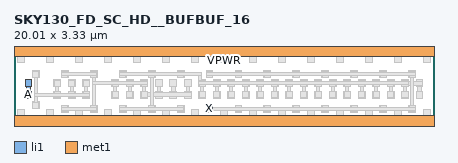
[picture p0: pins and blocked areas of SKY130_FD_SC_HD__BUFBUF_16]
MACRO SKY130_FD_SC_HD__BUFBUF_16
 CLASS CORE ;
 FOREIGN SKY130_FD_SC_HD__BUFBUF_16 0 0 ;
 SIZE 20.01 BY 3.33 ;
 ORIGIN 0 0 ;
 SYMMETRY X Y R90 ;
 SITE unit ;
  PIN VPWR
   DIRECTION INOUT ;
   USE POWER ;
   SHAPE ABUTMENT ;
    PORT
     CLASS CORE ;
       LAYER li1 ;
        RECT 0.00000000 3.09000000 20.01000000 3.57000000 ;
       LAYER met1 ;
        RECT 0.00000000 3.09000000 20.01000000 3.57000000 ;
    END
  END VPWR

  PIN VGND
   DIRECTION INOUT ;
   USE POWER ;
   SHAPE ABUTMENT ;
    PORT
     CLASS CORE ;
       LAYER li1 ;
        RECT 0.00000000 -0.24000000 20.01000000 0.24000000 ;
       LAYER met1 ;
        RECT 0.00000000 -0.24000000 20.01000000 0.24000000 ;
    END
  END VGND

  PIN X
   DIRECTION INOUT ;
   USE SIGNAL ;
   SHAPE ABUTMENT ;
    PORT
     CLASS CORE ;
       LAYER li1 ;
        RECT 9.15000000 0.42000000 9.48000000 0.75000000 ;
    END
  END X

  PIN A
   DIRECTION INOUT ;
   USE SIGNAL ;
   SHAPE ABUTMENT ;
    PORT
     CLASS CORE ;
       LAYER li1 ;
        RECT 0.52500000 1.09500000 0.85500000 1.42500000 ;
        RECT 0.60500000 1.42500000 0.77500000 1.63500000 ;
        RECT 0.52500000 1.63500000 0.85500000 1.96500000 ;
    END
  END A

 OBS
    LAYER polycont ;
     RECT 0.60500000 1.17500000 0.77500000 1.34500000 ;
     RECT 1.98500000 1.17500000 2.15500000 1.34500000 ;
     RECT 2.67500000 1.17500000 2.84500000 1.34500000 ;
     RECT 3.36500000 1.17500000 3.53500000 1.34500000 ;
     RECT 4.74500000 1.17500000 4.91500000 1.34500000 ;
     RECT 5.43500000 1.17500000 5.60500000 1.34500000 ;
     RECT 6.12500000 1.17500000 6.29500000 1.34500000 ;
     RECT 6.81500000 1.17500000 6.98500000 1.34500000 ;
     RECT 7.50500000 1.17500000 7.67500000 1.34500000 ;
     RECT 8.19500000 1.17500000 8.36500000 1.34500000 ;
     RECT 8.88500000 1.17500000 9.05500000 1.34500000 ;
     RECT 9.57500000 1.17500000 9.74500000 1.34500000 ;
     RECT 10.26500000 1.17500000 10.43500000 1.34500000 ;
     RECT 10.95500000 1.17500000 11.12500000 1.34500000 ;
     RECT 11.64500000 1.17500000 11.81500000 1.34500000 ;
     RECT 12.33500000 1.17500000 12.50500000 1.34500000 ;
     RECT 13.02500000 1.17500000 13.19500000 1.34500000 ;
     RECT 13.71500000 1.17500000 13.88500000 1.34500000 ;
     RECT 14.40500000 1.17500000 14.57500000 1.34500000 ;
     RECT 15.09500000 1.17500000 15.26500000 1.34500000 ;
     RECT 15.78500000 1.17500000 15.95500000 1.34500000 ;
     RECT 16.47500000 1.17500000 16.64500000 1.34500000 ;
     RECT 17.16500000 1.17500000 17.33500000 1.34500000 ;
     RECT 17.85500000 1.17500000 18.02500000 1.34500000 ;
     RECT 18.54500000 1.17500000 18.71500000 1.34500000 ;
     RECT 19.23500000 1.17500000 19.40500000 1.34500000 ;
     RECT 0.60500000 1.71500000 0.77500000 1.88500000 ;
     RECT 1.98500000 1.71500000 2.15500000 1.88500000 ;
     RECT 2.67500000 1.71500000 2.84500000 1.88500000 ;
     RECT 3.36500000 1.71500000 3.53500000 1.88500000 ;
     RECT 4.74500000 1.71500000 4.91500000 1.88500000 ;
     RECT 5.43500000 1.71500000 5.60500000 1.88500000 ;
     RECT 6.12500000 1.71500000 6.29500000 1.88500000 ;
     RECT 6.81500000 1.71500000 6.98500000 1.88500000 ;
     RECT 7.50500000 1.71500000 7.67500000 1.88500000 ;
     RECT 8.19500000 1.71500000 8.36500000 1.88500000 ;
     RECT 8.88500000 1.71500000 9.05500000 1.88500000 ;
     RECT 9.57500000 1.71500000 9.74500000 1.88500000 ;
     RECT 10.26500000 1.71500000 10.43500000 1.88500000 ;
     RECT 10.95500000 1.71500000 11.12500000 1.88500000 ;
     RECT 11.64500000 1.71500000 11.81500000 1.88500000 ;
     RECT 12.33500000 1.71500000 12.50500000 1.88500000 ;
     RECT 13.02500000 1.71500000 13.19500000 1.88500000 ;
     RECT 13.71500000 1.71500000 13.88500000 1.88500000 ;
     RECT 14.40500000 1.71500000 14.57500000 1.88500000 ;
     RECT 15.09500000 1.71500000 15.26500000 1.88500000 ;
     RECT 15.78500000 1.71500000 15.95500000 1.88500000 ;
     RECT 16.47500000 1.71500000 16.64500000 1.88500000 ;
     RECT 17.16500000 1.71500000 17.33500000 1.88500000 ;
     RECT 17.85500000 1.71500000 18.02500000 1.88500000 ;
     RECT 18.54500000 1.71500000 18.71500000 1.88500000 ;
     RECT 19.23500000 1.71500000 19.40500000 1.88500000 ;

    LAYER pdiffc ;
     RECT 0.95000000 2.15000000 1.12000000 2.32000000 ;
     RECT 2.33000000 2.15000000 2.50000000 2.32000000 ;
     RECT 3.71000000 2.15000000 3.88000000 2.32000000 ;
     RECT 5.09000000 2.15000000 5.26000000 2.32000000 ;
     RECT 6.47000000 2.15000000 6.64000000 2.32000000 ;
     RECT 7.85000000 2.15000000 8.02000000 2.32000000 ;
     RECT 9.23000000 2.15000000 9.40000000 2.32000000 ;
     RECT 10.61000000 2.15000000 10.78000000 2.32000000 ;
     RECT 11.99000000 2.15000000 12.16000000 2.32000000 ;
     RECT 13.37000000 2.15000000 13.54000000 2.32000000 ;
     RECT 14.75000000 2.15000000 14.92000000 2.32000000 ;
     RECT 16.13000000 2.15000000 16.30000000 2.32000000 ;
     RECT 17.51000000 2.15000000 17.68000000 2.32000000 ;
     RECT 18.89000000 2.15000000 19.06000000 2.32000000 ;
     RECT 0.26000000 2.86000000 0.43000000 3.03000000 ;
     RECT 1.64000000 2.86000000 1.81000000 3.03000000 ;
     RECT 3.02000000 2.86000000 3.19000000 3.03000000 ;
     RECT 4.40000000 2.86000000 4.57000000 3.03000000 ;
     RECT 5.78000000 2.86000000 5.95000000 3.03000000 ;
     RECT 7.16000000 2.86000000 7.33000000 3.03000000 ;
     RECT 8.54000000 2.86000000 8.71000000 3.03000000 ;
     RECT 9.92000000 2.86000000 10.09000000 3.03000000 ;
     RECT 11.30000000 2.86000000 11.47000000 3.03000000 ;
     RECT 12.68000000 2.86000000 12.85000000 3.03000000 ;
     RECT 14.06000000 2.86000000 14.23000000 3.03000000 ;
     RECT 15.44000000 2.86000000 15.61000000 3.03000000 ;
     RECT 16.82000000 2.86000000 16.99000000 3.03000000 ;
     RECT 18.20000000 2.86000000 18.37000000 3.03000000 ;
     RECT 19.58000000 2.86000000 19.75000000 3.03000000 ;

    LAYER ndiffc ;
     RECT 0.26000000 0.30000000 0.43000000 0.47000000 ;
     RECT 1.64000000 0.30000000 1.81000000 0.47000000 ;
     RECT 3.02000000 0.30000000 3.19000000 0.47000000 ;
     RECT 4.40000000 0.30000000 4.57000000 0.47000000 ;
     RECT 5.78000000 0.30000000 5.95000000 0.47000000 ;
     RECT 7.16000000 0.30000000 7.33000000 0.47000000 ;
     RECT 8.54000000 0.30000000 8.71000000 0.47000000 ;
     RECT 9.92000000 0.30000000 10.09000000 0.47000000 ;
     RECT 11.30000000 0.30000000 11.47000000 0.47000000 ;
     RECT 12.68000000 0.30000000 12.85000000 0.47000000 ;
     RECT 14.06000000 0.30000000 14.23000000 0.47000000 ;
     RECT 15.44000000 0.30000000 15.61000000 0.47000000 ;
     RECT 16.82000000 0.30000000 16.99000000 0.47000000 ;
     RECT 18.20000000 0.30000000 18.37000000 0.47000000 ;
     RECT 19.58000000 0.30000000 19.75000000 0.47000000 ;
     RECT 2.33000000 0.50000000 2.50000000 0.67000000 ;
     RECT 3.71000000 0.50000000 3.88000000 0.67000000 ;
     RECT 5.09000000 0.50000000 5.26000000 0.67000000 ;
     RECT 6.47000000 0.50000000 6.64000000 0.67000000 ;
     RECT 7.85000000 0.50000000 8.02000000 0.67000000 ;
     RECT 9.23000000 0.50000000 9.40000000 0.67000000 ;
     RECT 10.61000000 0.50000000 10.78000000 0.67000000 ;
     RECT 11.99000000 0.50000000 12.16000000 0.67000000 ;
     RECT 13.37000000 0.50000000 13.54000000 0.67000000 ;
     RECT 14.75000000 0.50000000 14.92000000 0.67000000 ;
     RECT 16.13000000 0.50000000 16.30000000 0.67000000 ;
     RECT 17.51000000 0.50000000 17.68000000 0.67000000 ;
     RECT 18.89000000 0.50000000 19.06000000 0.67000000 ;
     RECT 0.95000000 0.66000000 1.12000000 0.83000000 ;

    LAYER li1 ;
     RECT 0.00000000 -0.24000000 20.01000000 0.24000000 ;
     RECT 9.84000000 0.24000000 10.17000000 0.55000000 ;
     RECT 9.84000000 2.78000000 10.17000000 3.09000000 ;
     RECT 0.00000000 3.09000000 20.01000000 3.57000000 ;
     RECT 13.98000000 0.24000000 14.31000000 0.55000000 ;
     RECT 15.36000000 0.24000000 15.69000000 0.55000000 ;
     RECT 16.74000000 0.24000000 17.07000000 0.55000000 ;
     RECT 18.12000000 0.24000000 18.45000000 0.55000000 ;
     RECT 19.50000000 0.24000000 19.83000000 0.55000000 ;
     RECT 10.53000000 0.42000000 10.86000000 0.75000000 ;
     RECT 11.91000000 0.42000000 12.24000000 0.75000000 ;
     RECT 13.29000000 0.42000000 13.62000000 0.75000000 ;
     RECT 14.67000000 0.42000000 15.00000000 0.75000000 ;
     RECT 16.05000000 0.42000000 16.38000000 0.75000000 ;
     RECT 17.43000000 0.42000000 17.76000000 0.75000000 ;
     RECT 18.81000000 0.42000000 19.14000000 0.75000000 ;
     RECT 10.18500000 1.09500000 10.51500000 1.42500000 ;
     RECT 10.87500000 1.09500000 11.20500000 1.42500000 ;
     RECT 11.56500000 1.09500000 11.89500000 1.42500000 ;
     RECT 12.25500000 1.09500000 12.58500000 1.42500000 ;
     RECT 12.94500000 1.09500000 13.27500000 1.42500000 ;
     RECT 13.63500000 1.09500000 13.96500000 1.42500000 ;
     RECT 14.32500000 1.09500000 14.65500000 1.42500000 ;
     RECT 15.01500000 1.09500000 15.34500000 1.42500000 ;
     RECT 15.70500000 1.09500000 16.03500000 1.42500000 ;
     RECT 16.39500000 1.09500000 16.72500000 1.42500000 ;
     RECT 17.08500000 1.09500000 17.41500000 1.42500000 ;
     RECT 17.77500000 1.09500000 18.10500000 1.42500000 ;
     RECT 18.46500000 1.09500000 18.79500000 1.42500000 ;
     RECT 10.18500000 1.63500000 10.51500000 1.96500000 ;
     RECT 10.87500000 1.63500000 11.20500000 1.96500000 ;
     RECT 11.56500000 1.63500000 11.89500000 1.96500000 ;
     RECT 12.25500000 1.63500000 12.58500000 1.96500000 ;
     RECT 12.94500000 1.63500000 13.27500000 1.96500000 ;
     RECT 13.63500000 1.63500000 13.96500000 1.96500000 ;
     RECT 14.32500000 1.63500000 14.65500000 1.96500000 ;
     RECT 15.01500000 1.63500000 15.34500000 1.96500000 ;
     RECT 15.70500000 1.63500000 16.03500000 1.96500000 ;
     RECT 16.39500000 1.63500000 16.72500000 1.96500000 ;
     RECT 17.08500000 1.63500000 17.41500000 1.96500000 ;
     RECT 17.77500000 1.63500000 18.10500000 1.96500000 ;
     RECT 19.15500000 1.09500000 19.48500000 1.42500000 ;
     RECT 19.23500000 1.42500000 19.40500000 1.63500000 ;
     RECT 18.46500000 1.63500000 18.79500000 1.71500000 ;
     RECT 19.15500000 1.63500000 19.48500000 1.71500000 ;
     RECT 18.46500000 1.71500000 19.48500000 1.88500000 ;
     RECT 18.46500000 1.88500000 18.79500000 1.96500000 ;
     RECT 19.15500000 1.88500000 19.48500000 1.96500000 ;
     RECT 10.53000000 2.07000000 10.86000000 2.40000000 ;
     RECT 11.91000000 2.07000000 12.24000000 2.40000000 ;
     RECT 13.29000000 2.07000000 13.62000000 2.40000000 ;
     RECT 14.67000000 2.07000000 15.00000000 2.40000000 ;
     RECT 16.05000000 2.07000000 16.38000000 2.40000000 ;
     RECT 17.43000000 2.07000000 17.76000000 2.40000000 ;
     RECT 18.81000000 2.07000000 19.14000000 2.40000000 ;
     RECT 11.22000000 0.24000000 11.55000000 0.55000000 ;
     RECT 11.22000000 2.78000000 11.55000000 3.09000000 ;
     RECT 12.60000000 2.78000000 12.93000000 3.09000000 ;
     RECT 13.98000000 2.78000000 14.31000000 3.09000000 ;
     RECT 15.36000000 2.78000000 15.69000000 3.09000000 ;
     RECT 16.74000000 2.78000000 17.07000000 3.09000000 ;
     RECT 18.12000000 2.78000000 18.45000000 3.09000000 ;
     RECT 19.50000000 2.78000000 19.83000000 3.09000000 ;
     RECT 12.60000000 0.24000000 12.93000000 0.55000000 ;
     RECT 6.04500000 1.34500000 6.37500000 1.42500000 ;
     RECT 6.73500000 1.34500000 7.06500000 1.42500000 ;
     RECT 7.42500000 1.34500000 7.75500000 1.42500000 ;
     RECT 8.11500000 1.34500000 8.44500000 1.42500000 ;
     RECT 6.81500000 1.42500000 6.98500000 1.63500000 ;
     RECT 7.50500000 1.42500000 7.67500000 1.63500000 ;
     RECT 8.19500000 1.42500000 8.36500000 1.63500000 ;
     RECT 6.73500000 1.63500000 7.06500000 1.96500000 ;
     RECT 7.42500000 1.63500000 7.75500000 1.96500000 ;
     RECT 8.11500000 1.63500000 8.44500000 1.96500000 ;
     RECT 8.80500000 1.63500000 9.13500000 1.96500000 ;
     RECT 9.49500000 1.63500000 9.82500000 1.96500000 ;
     RECT 0.87000000 0.58000000 1.20000000 0.91000000 ;
     RECT 1.90500000 1.09500000 2.23500000 1.42500000 ;
     RECT 2.59500000 1.09500000 2.92500000 1.42500000 ;
     RECT 3.28500000 1.09500000 3.61500000 1.42500000 ;
     RECT 4.66500000 1.09500000 4.99500000 1.42500000 ;
     RECT 5.35500000 1.09500000 5.68500000 1.42500000 ;
     RECT 8.80500000 1.09500000 9.13500000 1.42500000 ;
     RECT 9.49500000 1.09500000 9.82500000 1.42500000 ;
     RECT 2.25000000 0.42000000 2.58000000 0.75000000 ;
     RECT 3.63000000 0.42000000 3.96000000 0.75000000 ;
     RECT 5.01000000 0.42000000 5.34000000 0.75000000 ;
     RECT 6.39000000 0.42000000 6.72000000 0.75000000 ;
     RECT 7.77000000 0.42000000 8.10000000 0.75000000 ;
     RECT 9.15000000 0.42000000 9.48000000 0.75000000 ;
     RECT 1.56000000 0.24000000 1.89000000 0.55000000 ;
     RECT 2.94000000 0.24000000 3.27000000 0.55000000 ;
     RECT 4.32000000 0.24000000 4.65000000 0.55000000 ;
     RECT 5.70000000 0.24000000 6.03000000 0.55000000 ;
     RECT 7.08000000 0.24000000 7.41000000 0.55000000 ;
     RECT 0.87000000 2.07000000 1.20000000 2.40000000 ;
     RECT 2.25000000 2.07000000 2.58000000 2.40000000 ;
     RECT 3.63000000 2.07000000 3.96000000 2.40000000 ;
     RECT 5.01000000 2.07000000 5.34000000 2.40000000 ;
     RECT 6.39000000 2.07000000 6.72000000 2.40000000 ;
     RECT 7.77000000 2.07000000 8.10000000 2.40000000 ;
     RECT 9.15000000 2.07000000 9.48000000 2.40000000 ;
     RECT 8.46000000 0.24000000 8.79000000 0.55000000 ;
     RECT 0.18000000 0.24000000 0.51000000 0.55000000 ;
     RECT 0.52500000 1.09500000 0.85500000 1.42500000 ;
     RECT 0.60500000 1.42500000 0.77500000 1.63500000 ;
     RECT 0.52500000 1.63500000 0.85500000 1.96500000 ;
     RECT 1.90500000 1.63500000 2.23500000 1.96500000 ;
     RECT 2.59500000 1.63500000 2.92500000 1.96500000 ;
     RECT 0.18000000 2.78000000 0.51000000 3.09000000 ;
     RECT 1.56000000 2.78000000 1.89000000 3.09000000 ;
     RECT 2.94000000 2.78000000 3.27000000 3.09000000 ;
     RECT 4.32000000 2.78000000 4.65000000 3.09000000 ;
     RECT 5.70000000 2.78000000 6.03000000 3.09000000 ;
     RECT 7.08000000 2.78000000 7.41000000 3.09000000 ;
     RECT 8.46000000 2.78000000 8.79000000 3.09000000 ;
     RECT 3.28500000 1.63500000 3.61500000 1.96500000 ;
     RECT 4.66500000 1.63500000 4.99500000 1.96500000 ;
     RECT 5.35500000 1.63500000 5.68500000 1.96500000 ;
     RECT 6.04500000 1.63500000 6.37500000 1.96500000 ;
     RECT 6.04500000 1.09500000 6.37500000 1.17500000 ;
     RECT 6.73500000 1.09500000 7.06500000 1.17500000 ;
     RECT 7.42500000 1.09500000 7.75500000 1.17500000 ;
     RECT 8.11500000 1.09500000 8.44500000 1.17500000 ;
     RECT 6.04500000 1.17500000 8.44500000 1.34500000 ;

    LAYER viali ;
     RECT 9.92000000 -0.08500000 10.09000000 0.08500000 ;
     RECT 2.33000000 0.50000000 2.50000000 0.67000000 ;
     RECT 3.71000000 0.50000000 3.88000000 0.67000000 ;
     RECT 5.09000000 0.50000000 5.26000000 0.67000000 ;
     RECT 6.47000000 0.50000000 6.64000000 0.67000000 ;
     RECT 7.85000000 0.50000000 8.02000000 0.67000000 ;
     RECT 9.23000000 0.50000000 9.40000000 0.67000000 ;
     RECT 10.61000000 0.50000000 10.78000000 0.67000000 ;
     RECT 11.99000000 0.50000000 12.16000000 0.67000000 ;
     RECT 13.37000000 0.50000000 13.54000000 0.67000000 ;
     RECT 14.75000000 0.50000000 14.92000000 0.67000000 ;
     RECT 16.13000000 0.50000000 16.30000000 0.67000000 ;
     RECT 17.51000000 0.50000000 17.68000000 0.67000000 ;
     RECT 18.89000000 0.50000000 19.06000000 0.67000000 ;
     RECT 0.95000000 0.66000000 1.12000000 0.83000000 ;
     RECT 1.98500000 1.17500000 2.15500000 1.34500000 ;
     RECT 2.67500000 1.17500000 2.84500000 1.34500000 ;
     RECT 3.36500000 1.17500000 3.53500000 1.34500000 ;
     RECT 4.74500000 1.17500000 4.91500000 1.34500000 ;
     RECT 5.43500000 1.17500000 5.60500000 1.34500000 ;
     RECT 6.12500000 1.17500000 6.29500000 1.34500000 ;
     RECT 8.88500000 1.17500000 9.05500000 1.34500000 ;
     RECT 9.57500000 1.17500000 9.74500000 1.34500000 ;
     RECT 10.26500000 1.17500000 10.43500000 1.34500000 ;
     RECT 10.95500000 1.17500000 11.12500000 1.34500000 ;
     RECT 11.64500000 1.17500000 11.81500000 1.34500000 ;
     RECT 12.33500000 1.17500000 12.50500000 1.34500000 ;
     RECT 13.02500000 1.17500000 13.19500000 1.34500000 ;
     RECT 13.71500000 1.17500000 13.88500000 1.34500000 ;
     RECT 14.40500000 1.17500000 14.57500000 1.34500000 ;
     RECT 15.09500000 1.17500000 15.26500000 1.34500000 ;
     RECT 15.78500000 1.17500000 15.95500000 1.34500000 ;
     RECT 16.47500000 1.17500000 16.64500000 1.34500000 ;
     RECT 17.16500000 1.17500000 17.33500000 1.34500000 ;
     RECT 17.85500000 1.17500000 18.02500000 1.34500000 ;
     RECT 18.54500000 1.17500000 18.71500000 1.34500000 ;
     RECT 1.98500000 1.71500000 2.15500000 1.88500000 ;
     RECT 2.67500000 1.71500000 2.84500000 1.88500000 ;
     RECT 3.36500000 1.71500000 3.53500000 1.88500000 ;
     RECT 4.74500000 1.71500000 4.91500000 1.88500000 ;
     RECT 5.43500000 1.71500000 5.60500000 1.88500000 ;
     RECT 6.12500000 1.71500000 6.29500000 1.88500000 ;
     RECT 8.88500000 1.71500000 9.05500000 1.88500000 ;
     RECT 9.57500000 1.71500000 9.74500000 1.88500000 ;
     RECT 10.26500000 1.71500000 10.43500000 1.88500000 ;
     RECT 10.95500000 1.71500000 11.12500000 1.88500000 ;
     RECT 11.64500000 1.71500000 11.81500000 1.88500000 ;
     RECT 12.33500000 1.71500000 12.50500000 1.88500000 ;
     RECT 13.02500000 1.71500000 13.19500000 1.88500000 ;
     RECT 13.71500000 1.71500000 13.88500000 1.88500000 ;
     RECT 14.40500000 1.71500000 14.57500000 1.88500000 ;
     RECT 15.09500000 1.71500000 15.26500000 1.88500000 ;
     RECT 15.78500000 1.71500000 15.95500000 1.88500000 ;
     RECT 16.47500000 1.71500000 16.64500000 1.88500000 ;
     RECT 17.16500000 1.71500000 17.33500000 1.88500000 ;
     RECT 17.85500000 1.71500000 18.02500000 1.88500000 ;
     RECT 18.54500000 1.71500000 18.71500000 1.88500000 ;
     RECT 0.95000000 2.15000000 1.12000000 2.32000000 ;
     RECT 2.33000000 2.15000000 2.50000000 2.32000000 ;
     RECT 3.71000000 2.15000000 3.88000000 2.32000000 ;
     RECT 5.09000000 2.15000000 5.26000000 2.32000000 ;
     RECT 6.47000000 2.15000000 6.64000000 2.32000000 ;
     RECT 7.85000000 2.15000000 8.02000000 2.32000000 ;
     RECT 9.23000000 2.15000000 9.40000000 2.32000000 ;
     RECT 10.61000000 2.15000000 10.78000000 2.32000000 ;
     RECT 11.99000000 2.15000000 12.16000000 2.32000000 ;
     RECT 13.37000000 2.15000000 13.54000000 2.32000000 ;
     RECT 14.75000000 2.15000000 14.92000000 2.32000000 ;
     RECT 16.13000000 2.15000000 16.30000000 2.32000000 ;
     RECT 17.51000000 2.15000000 17.68000000 2.32000000 ;
     RECT 18.89000000 2.15000000 19.06000000 2.32000000 ;
     RECT 4.40000000 3.24500000 4.57000000 3.41500000 ;

    LAYER met1 ;
     RECT 0.00000000 -0.24000000 20.01000000 0.24000000 ;
     RECT 8.78500000 1.73000000 18.77500000 1.87000000 ;
     RECT 9.17000000 0.51500000 19.12000000 0.65500000 ;
     RECT 9.17000000 2.16500000 19.12000000 2.30500000 ;
     RECT 0.00000000 3.09000000 20.01000000 3.57000000 ;
     RECT 12.96500000 1.11500000 13.25500000 1.40500000 ;
     RECT 13.65500000 1.11500000 13.94500000 1.40500000 ;
     RECT 14.34500000 1.11500000 14.63500000 1.40500000 ;
     RECT 15.03500000 1.11500000 15.32500000 1.40500000 ;
     RECT 15.72500000 1.11500000 16.01500000 1.40500000 ;
     RECT 16.41500000 1.11500000 16.70500000 1.40500000 ;
     RECT 17.10500000 1.11500000 17.39500000 1.40500000 ;
     RECT 17.79500000 1.11500000 18.08500000 1.40500000 ;
     RECT 18.48500000 1.11500000 18.77500000 1.40500000 ;
     RECT 10.28000000 1.40500000 10.42000000 1.65500000 ;
     RECT 10.97000000 1.40500000 11.11000000 1.65500000 ;
     RECT 11.66000000 1.40500000 11.80000000 1.65500000 ;
     RECT 12.35000000 1.40500000 12.49000000 1.65500000 ;
     RECT 13.04000000 1.40500000 13.18000000 1.65500000 ;
     RECT 13.73000000 1.40500000 13.87000000 1.65500000 ;
     RECT 14.42000000 1.40500000 14.56000000 1.65500000 ;
     RECT 15.11000000 1.40500000 15.25000000 1.65500000 ;
     RECT 15.80000000 1.40500000 15.94000000 1.65500000 ;
     RECT 16.49000000 1.40500000 16.63000000 1.65500000 ;
     RECT 17.18000000 1.40500000 17.32000000 1.65500000 ;
     RECT 17.87000000 1.40500000 18.01000000 1.65500000 ;
     RECT 18.56000000 1.40500000 18.70000000 1.65500000 ;
     RECT 10.20500000 1.65500000 10.49500000 1.73000000 ;
     RECT 10.89500000 1.65500000 11.18500000 1.73000000 ;
     RECT 11.58500000 1.65500000 11.87500000 1.73000000 ;
     RECT 12.27500000 1.65500000 12.56500000 1.73000000 ;
     RECT 12.96500000 1.65500000 13.25500000 1.73000000 ;
     RECT 13.65500000 1.65500000 13.94500000 1.73000000 ;
     RECT 14.34500000 1.65500000 14.63500000 1.73000000 ;
     RECT 15.03500000 1.65500000 15.32500000 1.73000000 ;
     RECT 15.72500000 1.65500000 16.01500000 1.73000000 ;
     RECT 16.41500000 1.65500000 16.70500000 1.73000000 ;
     RECT 17.10500000 1.65500000 17.39500000 1.73000000 ;
     RECT 17.79500000 1.65500000 18.08500000 1.73000000 ;
     RECT 18.48500000 1.65500000 18.77500000 1.73000000 ;
     RECT 10.20500000 1.11500000 10.49500000 1.40500000 ;
     RECT 10.20500000 1.87000000 10.49500000 1.94500000 ;
     RECT 10.89500000 1.87000000 11.18500000 1.94500000 ;
     RECT 11.58500000 1.87000000 11.87500000 1.94500000 ;
     RECT 12.27500000 1.87000000 12.56500000 1.94500000 ;
     RECT 12.96500000 1.87000000 13.25500000 1.94500000 ;
     RECT 13.65500000 1.87000000 13.94500000 1.94500000 ;
     RECT 14.34500000 1.87000000 14.63500000 1.94500000 ;
     RECT 15.03500000 1.87000000 15.32500000 1.94500000 ;
     RECT 15.72500000 1.87000000 16.01500000 1.94500000 ;
     RECT 16.41500000 1.87000000 16.70500000 1.94500000 ;
     RECT 17.10500000 1.87000000 17.39500000 1.94500000 ;
     RECT 17.79500000 1.87000000 18.08500000 1.94500000 ;
     RECT 18.48500000 1.87000000 18.77500000 1.94500000 ;
     RECT 10.55000000 0.44000000 10.84000000 0.51500000 ;
     RECT 11.93000000 0.44000000 12.22000000 0.51500000 ;
     RECT 13.31000000 0.44000000 13.60000000 0.51500000 ;
     RECT 14.69000000 0.44000000 14.98000000 0.51500000 ;
     RECT 16.07000000 0.44000000 16.36000000 0.51500000 ;
     RECT 17.45000000 0.44000000 17.74000000 0.51500000 ;
     RECT 18.83000000 0.44000000 19.12000000 0.51500000 ;
     RECT 10.89500000 1.11500000 11.18500000 1.40500000 ;
     RECT 10.55000000 0.65500000 10.84000000 0.73000000 ;
     RECT 11.93000000 0.65500000 12.22000000 0.73000000 ;
     RECT 13.31000000 0.65500000 13.60000000 0.73000000 ;
     RECT 14.69000000 0.65500000 14.98000000 0.73000000 ;
     RECT 16.07000000 0.65500000 16.36000000 0.73000000 ;
     RECT 17.45000000 0.65500000 17.74000000 0.73000000 ;
     RECT 18.83000000 0.65500000 19.12000000 0.73000000 ;
     RECT 18.90500000 0.73000000 19.04500000 2.09000000 ;
     RECT 10.55000000 2.09000000 10.84000000 2.16500000 ;
     RECT 11.93000000 2.09000000 12.22000000 2.16500000 ;
     RECT 13.31000000 2.09000000 13.60000000 2.16500000 ;
     RECT 14.69000000 2.09000000 14.98000000 2.16500000 ;
     RECT 16.07000000 2.09000000 16.36000000 2.16500000 ;
     RECT 17.45000000 2.09000000 17.74000000 2.16500000 ;
     RECT 18.83000000 2.09000000 19.12000000 2.16500000 ;
     RECT 11.58500000 1.11500000 11.87500000 1.40500000 ;
     RECT 10.55000000 2.30500000 10.84000000 2.38000000 ;
     RECT 11.93000000 2.30500000 12.22000000 2.38000000 ;
     RECT 13.31000000 2.30500000 13.60000000 2.38000000 ;
     RECT 14.69000000 2.30500000 14.98000000 2.38000000 ;
     RECT 16.07000000 2.30500000 16.36000000 2.38000000 ;
     RECT 17.45000000 2.30500000 17.74000000 2.38000000 ;
     RECT 18.83000000 2.30500000 19.12000000 2.38000000 ;
     RECT 12.27500000 1.11500000 12.56500000 1.40500000 ;
     RECT 5.37500000 1.65500000 5.66500000 1.73000000 ;
     RECT 6.06500000 1.65500000 6.35500000 1.73000000 ;
     RECT 3.72500000 1.73000000 6.35500000 1.87000000 ;
     RECT 4.68500000 1.87000000 4.97500000 1.94500000 ;
     RECT 5.37500000 1.87000000 5.66500000 1.94500000 ;
     RECT 6.06500000 1.87000000 6.35500000 1.94500000 ;
     RECT 3.72500000 1.87000000 3.86500000 2.09000000 ;
     RECT 2.27000000 2.09000000 2.56000000 2.16500000 ;
     RECT 3.65000000 2.09000000 3.94000000 2.16500000 ;
     RECT 2.27000000 2.16500000 3.94000000 2.30500000 ;
     RECT 8.78500000 1.87000000 9.11500000 1.94500000 ;
     RECT 9.51500000 1.87000000 9.80500000 1.94500000 ;
     RECT 2.27000000 2.30500000 2.56000000 2.38000000 ;
     RECT 3.65000000 2.30500000 3.94000000 2.38000000 ;
     RECT 5.03000000 0.44000000 5.32000000 0.51500000 ;
     RECT 6.41000000 0.44000000 6.70000000 0.51500000 ;
     RECT 7.79000000 0.44000000 8.08000000 0.51500000 ;
     RECT 5.03000000 0.51500000 8.08000000 0.65500000 ;
     RECT 5.03000000 0.65500000 5.32000000 0.73000000 ;
     RECT 6.41000000 0.65500000 6.70000000 0.73000000 ;
     RECT 7.79000000 0.65500000 8.08000000 0.73000000 ;
     RECT 8.82500000 1.11500000 9.11500000 1.40500000 ;
     RECT 9.51500000 1.11500000 9.80500000 1.40500000 ;
     RECT 0.89000000 0.60000000 1.18000000 0.89000000 ;
     RECT 0.96500000 0.89000000 1.10500000 1.19000000 ;
     RECT 6.48500000 0.73000000 6.62500000 2.09000000 ;
     RECT 5.03000000 2.09000000 5.32000000 2.16500000 ;
     RECT 6.41000000 2.09000000 6.70000000 2.16500000 ;
     RECT 7.79000000 2.09000000 8.08000000 2.16500000 ;
     RECT 8.78500000 1.94500000 8.92500000 2.16500000 ;
     RECT 5.03000000 2.16500000 8.92500000 2.30500000 ;
     RECT 5.03000000 2.30500000 5.32000000 2.38000000 ;
     RECT 6.41000000 2.30500000 6.70000000 2.38000000 ;
     RECT 7.79000000 2.30500000 8.08000000 2.38000000 ;
     RECT 9.17000000 0.44000000 9.46000000 0.51500000 ;
     RECT 1.92500000 1.11500000 2.21500000 1.19000000 ;
     RECT 2.61500000 1.11500000 2.90500000 1.19000000 ;
     RECT 3.30500000 1.11500000 3.59500000 1.19000000 ;
     RECT 0.96500000 1.19000000 3.59500000 1.33000000 ;
     RECT 1.92500000 1.33000000 2.21500000 1.40500000 ;
     RECT 2.61500000 1.33000000 2.90500000 1.40500000 ;
     RECT 3.30500000 1.33000000 3.59500000 1.40500000 ;
     RECT 2.00000000 1.40500000 2.14000000 1.65500000 ;
     RECT 9.17000000 0.65500000 9.46000000 0.73000000 ;
     RECT 2.69000000 1.40500000 2.83000000 1.65500000 ;
     RECT 3.38000000 1.40500000 3.52000000 1.65500000 ;
     RECT 1.92500000 1.65500000 2.21500000 1.94500000 ;
     RECT 8.90000000 1.40500000 9.04000000 1.65500000 ;
     RECT 9.59000000 1.40500000 9.73000000 1.65500000 ;
     RECT 2.61500000 1.65500000 2.90500000 1.94500000 ;
     RECT 3.30500000 1.65500000 3.59500000 1.94500000 ;
     RECT 0.96500000 1.33000000 1.10500000 2.09000000 ;
     RECT 9.17000000 2.09000000 9.46000000 2.16500000 ;
     RECT 0.89000000 2.09000000 1.18000000 2.38000000 ;
     RECT 2.27000000 0.44000000 2.56000000 0.51500000 ;
     RECT 3.65000000 0.44000000 3.94000000 0.51500000 ;
     RECT 2.27000000 0.51500000 3.94000000 0.65500000 ;
     RECT 2.27000000 0.65500000 2.56000000 0.73000000 ;
     RECT 3.65000000 0.65500000 3.94000000 0.73000000 ;
     RECT 4.68500000 1.11500000 4.97500000 1.40500000 ;
     RECT 5.37500000 1.11500000 5.66500000 1.40500000 ;
     RECT 9.17000000 2.30500000 9.46000000 2.38000000 ;
     RECT 6.06500000 1.11500000 6.35500000 1.40500000 ;
     RECT 4.76000000 1.40500000 4.90000000 1.65500000 ;
     RECT 8.82500000 1.65500000 9.11500000 1.73000000 ;
     RECT 9.51500000 1.65500000 9.80500000 1.73000000 ;
     RECT 5.45000000 1.40500000 5.59000000 1.65500000 ;
     RECT 6.14000000 1.40500000 6.28000000 1.65500000 ;
     RECT 3.72500000 0.73000000 3.86500000 1.73000000 ;
     RECT 4.68500000 1.65500000 4.97500000 1.73000000 ;

    LAYER via ;


    LAYER met2 ;


    LAYER via2 ;


    LAYER met3 ;


 END
END SKY130_FD_SC_HD__BUFBUF_16
